VERSION 5.7 ;
BUSBITCHARS "[]" ;
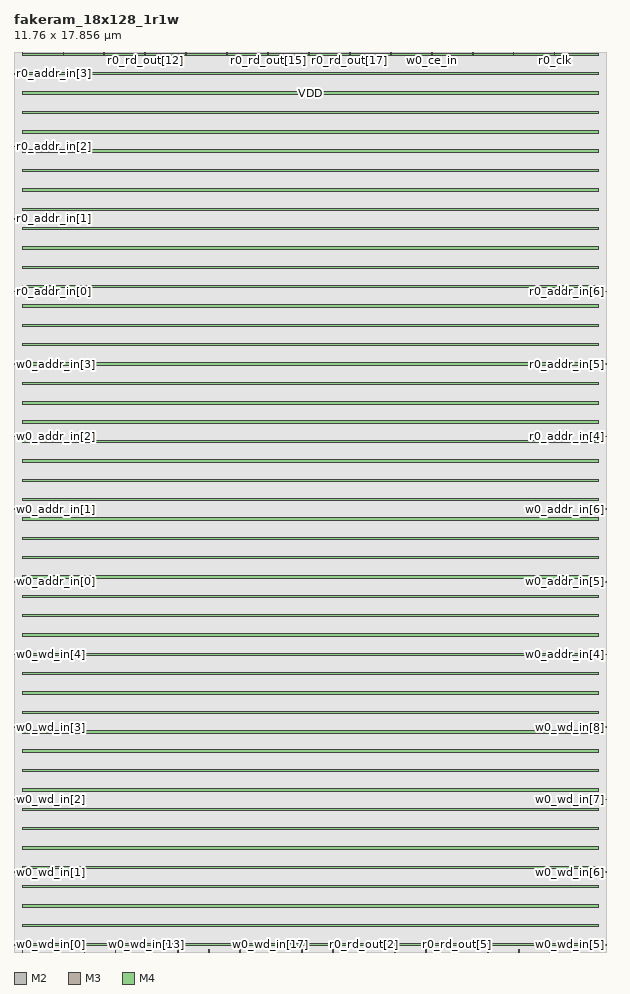
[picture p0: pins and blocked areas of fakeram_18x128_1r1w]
MACRO fakeram_18x128_1r1w
  FOREIGN fakeram_18x128_1r1w 0 0 ;
  SYMMETRY X Y R90 ;
  SIZE 11.760 BY 17.856 ;
  CLASS BLOCK ;
  PIN w0_wd_in[0]
    DIRECTION INPUT ;
    USE SIGNAL ;
    SHAPE ABUTMENT ;
    PORT
      LAYER M2 ;
      RECT 0.000 0.138 0.036 0.150 ;
    END
  END w0_wd_in[0]
  PIN w0_wd_in[1]
    DIRECTION INPUT ;
    USE SIGNAL ;
    SHAPE ABUTMENT ;
    PORT
      LAYER M2 ;
      RECT 0.000 1.578 0.036 1.590 ;
    END
  END w0_wd_in[1]
  PIN w0_wd_in[2]
    DIRECTION INPUT ;
    USE SIGNAL ;
    SHAPE ABUTMENT ;
    PORT
      LAYER M2 ;
      RECT 0.000 3.018 0.036 3.030 ;
    END
  END w0_wd_in[2]
  PIN w0_wd_in[3]
    DIRECTION INPUT ;
    USE SIGNAL ;
    SHAPE ABUTMENT ;
    PORT
      LAYER M2 ;
      RECT 0.000 4.458 0.036 4.470 ;
    END
  END w0_wd_in[3]
  PIN w0_wd_in[4]
    DIRECTION INPUT ;
    USE SIGNAL ;
    SHAPE ABUTMENT ;
    PORT
      LAYER M2 ;
      RECT 0.000 5.898 0.036 5.910 ;
    END
  END w0_wd_in[4]
  PIN w0_wd_in[5]
    DIRECTION INPUT ;
    USE SIGNAL ;
    SHAPE ABUTMENT ;
    PORT
      LAYER M2 ;
      RECT 11.724 0.138 11.760 0.150 ;
    END
  END w0_wd_in[5]
  PIN w0_wd_in[6]
    DIRECTION INPUT ;
    USE SIGNAL ;
    SHAPE ABUTMENT ;
    PORT
      LAYER M2 ;
      RECT 11.724 1.578 11.760 1.590 ;
    END
  END w0_wd_in[6]
  PIN w0_wd_in[7]
    DIRECTION INPUT ;
    USE SIGNAL ;
    SHAPE ABUTMENT ;
    PORT
      LAYER M2 ;
      RECT 11.724 3.018 11.760 3.030 ;
    END
  END w0_wd_in[7]
  PIN w0_wd_in[8]
    DIRECTION INPUT ;
    USE SIGNAL ;
    SHAPE ABUTMENT ;
    PORT
      LAYER M2 ;
      RECT 11.724 4.458 11.760 4.470 ;
    END
  END w0_wd_in[8]
  PIN w0_wd_in[9]
    DIRECTION INPUT ;
    USE SIGNAL ;
    SHAPE ABUTMENT ;
    PORT
      LAYER M3 ;
      RECT 0.161 0.000 0.175 0.042 ;
    END
  END w0_wd_in[9]
  PIN w0_wd_in[10]
    DIRECTION INPUT ;
    USE SIGNAL ;
    SHAPE ABUTMENT ;
    PORT
      LAYER M3 ;
      RECT 0.777 0.000 0.791 0.042 ;
    END
  END w0_wd_in[10]
  PIN w0_wd_in[11]
    DIRECTION INPUT ;
    USE SIGNAL ;
    SHAPE ABUTMENT ;
    PORT
      LAYER M3 ;
      RECT 1.393 0.000 1.407 0.042 ;
    END
  END w0_wd_in[11]
  PIN w0_wd_in[12]
    DIRECTION INPUT ;
    USE SIGNAL ;
    SHAPE ABUTMENT ;
    PORT
      LAYER M3 ;
      RECT 2.009 0.000 2.023 0.042 ;
    END
  END w0_wd_in[12]
  PIN w0_wd_in[13]
    DIRECTION INPUT ;
    USE SIGNAL ;
    SHAPE ABUTMENT ;
    PORT
      LAYER M3 ;
      RECT 2.625 0.000 2.639 0.042 ;
    END
  END w0_wd_in[13]
  PIN w0_wd_in[14]
    DIRECTION INPUT ;
    USE SIGNAL ;
    SHAPE ABUTMENT ;
    PORT
      LAYER M3 ;
      RECT 3.241 0.000 3.255 0.042 ;
    END
  END w0_wd_in[14]
  PIN w0_wd_in[15]
    DIRECTION INPUT ;
    USE SIGNAL ;
    SHAPE ABUTMENT ;
    PORT
      LAYER M3 ;
      RECT 3.857 0.000 3.871 0.042 ;
    END
  END w0_wd_in[15]
  PIN w0_wd_in[16]
    DIRECTION INPUT ;
    USE SIGNAL ;
    SHAPE ABUTMENT ;
    PORT
      LAYER M3 ;
      RECT 4.473 0.000 4.487 0.042 ;
    END
  END w0_wd_in[16]
  PIN w0_wd_in[17]
    DIRECTION INPUT ;
    USE SIGNAL ;
    SHAPE ABUTMENT ;
    PORT
      LAYER M3 ;
      RECT 5.089 0.000 5.103 0.042 ;
    END
  END w0_wd_in[17]
  PIN r0_rd_out[0]
    DIRECTION OUTPUT ;
    USE SIGNAL ;
    SHAPE ABUTMENT ;
    PORT
      LAYER M3 ;
      RECT 5.705 0.000 5.719 0.042 ;
    END
  END r0_rd_out[0]
  PIN r0_rd_out[1]
    DIRECTION OUTPUT ;
    USE SIGNAL ;
    SHAPE ABUTMENT ;
    PORT
      LAYER M3 ;
      RECT 6.321 0.000 6.335 0.042 ;
    END
  END r0_rd_out[1]
  PIN r0_rd_out[2]
    DIRECTION OUTPUT ;
    USE SIGNAL ;
    SHAPE ABUTMENT ;
    PORT
      LAYER M3 ;
      RECT 6.937 0.000 6.951 0.042 ;
    END
  END r0_rd_out[2]
  PIN r0_rd_out[3]
    DIRECTION OUTPUT ;
    USE SIGNAL ;
    SHAPE ABUTMENT ;
    PORT
      LAYER M3 ;
      RECT 7.553 0.000 7.567 0.042 ;
    END
  END r0_rd_out[3]
  PIN r0_rd_out[4]
    DIRECTION OUTPUT ;
    USE SIGNAL ;
    SHAPE ABUTMENT ;
    PORT
      LAYER M3 ;
      RECT 8.169 0.000 8.183 0.042 ;
    END
  END r0_rd_out[4]
  PIN r0_rd_out[5]
    DIRECTION OUTPUT ;
    USE SIGNAL ;
    SHAPE ABUTMENT ;
    PORT
      LAYER M3 ;
      RECT 8.785 0.000 8.799 0.042 ;
    END
  END r0_rd_out[5]
  PIN r0_rd_out[6]
    DIRECTION OUTPUT ;
    USE SIGNAL ;
    SHAPE ABUTMENT ;
    PORT
      LAYER M3 ;
      RECT 9.401 0.000 9.415 0.042 ;
    END
  END r0_rd_out[6]
  PIN r0_rd_out[7]
    DIRECTION OUTPUT ;
    USE SIGNAL ;
    SHAPE ABUTMENT ;
    PORT
      LAYER M3 ;
      RECT 10.017 0.000 10.031 0.042 ;
    END
  END r0_rd_out[7]
  PIN r0_rd_out[8]
    DIRECTION OUTPUT ;
    USE SIGNAL ;
    SHAPE ABUTMENT ;
    PORT
      LAYER M3 ;
      RECT 10.633 0.000 10.647 0.042 ;
    END
  END r0_rd_out[8]
  PIN r0_rd_out[9]
    DIRECTION OUTPUT ;
    USE SIGNAL ;
    SHAPE ABUTMENT ;
    PORT
      LAYER M3 ;
      RECT 0.161 17.814 0.175 17.856 ;
    END
  END r0_rd_out[9]
  PIN r0_rd_out[10]
    DIRECTION OUTPUT ;
    USE SIGNAL ;
    SHAPE ABUTMENT ;
    PORT
      LAYER M3 ;
      RECT 0.973 17.814 0.987 17.856 ;
    END
  END r0_rd_out[10]
  PIN r0_rd_out[11]
    DIRECTION OUTPUT ;
    USE SIGNAL ;
    SHAPE ABUTMENT ;
    PORT
      LAYER M3 ;
      RECT 1.785 17.814 1.799 17.856 ;
    END
  END r0_rd_out[11]
  PIN r0_rd_out[12]
    DIRECTION OUTPUT ;
    USE SIGNAL ;
    SHAPE ABUTMENT ;
    PORT
      LAYER M3 ;
      RECT 2.597 17.814 2.611 17.856 ;
    END
  END r0_rd_out[12]
  PIN r0_rd_out[13]
    DIRECTION OUTPUT ;
    USE SIGNAL ;
    SHAPE ABUTMENT ;
    PORT
      LAYER M3 ;
      RECT 3.409 17.814 3.423 17.856 ;
    END
  END r0_rd_out[13]
  PIN r0_rd_out[14]
    DIRECTION OUTPUT ;
    USE SIGNAL ;
    SHAPE ABUTMENT ;
    PORT
      LAYER M3 ;
      RECT 4.221 17.814 4.235 17.856 ;
    END
  END r0_rd_out[14]
  PIN r0_rd_out[15]
    DIRECTION OUTPUT ;
    USE SIGNAL ;
    SHAPE ABUTMENT ;
    PORT
      LAYER M3 ;
      RECT 5.033 17.814 5.047 17.856 ;
    END
  END r0_rd_out[15]
  PIN r0_rd_out[16]
    DIRECTION OUTPUT ;
    USE SIGNAL ;
    SHAPE ABUTMENT ;
    PORT
      LAYER M3 ;
      RECT 5.845 17.814 5.859 17.856 ;
    END
  END r0_rd_out[16]
  PIN r0_rd_out[17]
    DIRECTION OUTPUT ;
    USE SIGNAL ;
    SHAPE ABUTMENT ;
    PORT
      LAYER M3 ;
      RECT 6.657 17.814 6.671 17.856 ;
    END
  END r0_rd_out[17]
  PIN w0_addr_in[0]
    DIRECTION INPUT ;
    USE SIGNAL ;
    SHAPE ABUTMENT ;
    PORT
      LAYER M2 ;
      RECT 0.000 7.338 0.036 7.350 ;
    END
  END w0_addr_in[0]
  PIN w0_addr_in[1]
    DIRECTION INPUT ;
    USE SIGNAL ;
    SHAPE ABUTMENT ;
    PORT
      LAYER M2 ;
      RECT 0.000 8.778 0.036 8.790 ;
    END
  END w0_addr_in[1]
  PIN w0_addr_in[2]
    DIRECTION INPUT ;
    USE SIGNAL ;
    SHAPE ABUTMENT ;
    PORT
      LAYER M2 ;
      RECT 0.000 10.218 0.036 10.230 ;
    END
  END w0_addr_in[2]
  PIN w0_addr_in[3]
    DIRECTION INPUT ;
    USE SIGNAL ;
    SHAPE ABUTMENT ;
    PORT
      LAYER M2 ;
      RECT 0.000 11.658 0.036 11.670 ;
    END
  END w0_addr_in[3]
  PIN w0_addr_in[4]
    DIRECTION INPUT ;
    USE SIGNAL ;
    SHAPE ABUTMENT ;
    PORT
      LAYER M2 ;
      RECT 11.724 5.898 11.760 5.910 ;
    END
  END w0_addr_in[4]
  PIN w0_addr_in[5]
    DIRECTION INPUT ;
    USE SIGNAL ;
    SHAPE ABUTMENT ;
    PORT
      LAYER M2 ;
      RECT 11.724 7.338 11.760 7.350 ;
    END
  END w0_addr_in[5]
  PIN w0_addr_in[6]
    DIRECTION INPUT ;
    USE SIGNAL ;
    SHAPE ABUTMENT ;
    PORT
      LAYER M2 ;
      RECT 11.724 8.778 11.760 8.790 ;
    END
  END w0_addr_in[6]
  PIN r0_addr_in[0]
    DIRECTION INPUT ;
    USE SIGNAL ;
    SHAPE ABUTMENT ;
    PORT
      LAYER M2 ;
      RECT 0.000 13.098 0.036 13.110 ;
    END
  END r0_addr_in[0]
  PIN r0_addr_in[1]
    DIRECTION INPUT ;
    USE SIGNAL ;
    SHAPE ABUTMENT ;
    PORT
      LAYER M2 ;
      RECT 0.000 14.538 0.036 14.550 ;
    END
  END r0_addr_in[1]
  PIN r0_addr_in[2]
    DIRECTION INPUT ;
    USE SIGNAL ;
    SHAPE ABUTMENT ;
    PORT
      LAYER M2 ;
      RECT 0.000 15.978 0.036 15.990 ;
    END
  END r0_addr_in[2]
  PIN r0_addr_in[3]
    DIRECTION INPUT ;
    USE SIGNAL ;
    SHAPE ABUTMENT ;
    PORT
      LAYER M2 ;
      RECT 0.000 17.418 0.036 17.430 ;
    END
  END r0_addr_in[3]
  PIN r0_addr_in[4]
    DIRECTION INPUT ;
    USE SIGNAL ;
    SHAPE ABUTMENT ;
    PORT
      LAYER M2 ;
      RECT 11.724 10.218 11.760 10.230 ;
    END
  END r0_addr_in[4]
  PIN r0_addr_in[5]
    DIRECTION INPUT ;
    USE SIGNAL ;
    SHAPE ABUTMENT ;
    PORT
      LAYER M2 ;
      RECT 11.724 11.658 11.760 11.670 ;
    END
  END r0_addr_in[5]
  PIN r0_addr_in[6]
    DIRECTION INPUT ;
    USE SIGNAL ;
    SHAPE ABUTMENT ;
    PORT
      LAYER M2 ;
      RECT 11.724 13.098 11.760 13.110 ;
    END
  END r0_addr_in[6]
  PIN w0_we_in
    DIRECTION INPUT ;
    USE SIGNAL ;
    SHAPE ABUTMENT ;
    PORT
      LAYER M3 ;
      RECT 7.469 17.814 7.483 17.856 ;
    END
  END w0_we_in
  PIN w0_ce_in
    DIRECTION INPUT ;
    USE SIGNAL ;
    SHAPE ABUTMENT ;
    PORT
      LAYER M3 ;
      RECT 8.281 17.814 8.295 17.856 ;
    END
  END w0_ce_in
  PIN w0_clk
    DIRECTION INPUT ;
    USE SIGNAL ;
    SHAPE ABUTMENT ;
    PORT
      LAYER M3 ;
      RECT 9.093 17.814 9.107 17.856 ;
    END
  END w0_clk
  PIN r0_ce_in
    DIRECTION INPUT ;
    USE SIGNAL ;
    SHAPE ABUTMENT ;
    PORT
      LAYER M3 ;
      RECT 9.905 17.814 9.919 17.856 ;
    END
  END r0_ce_in
  PIN r0_clk
    DIRECTION INPUT ;
    USE SIGNAL ;
    SHAPE ABUTMENT ;
    PORT
      LAYER M3 ;
      RECT 10.717 17.814 10.731 17.856 ;
    END
  END r0_clk
  PIN VSS
    DIRECTION INOUT ;
    USE GROUND ;
    PORT
      LAYER M4 ;
      RECT 0.168 0.120 11.592 0.168 ;
      RECT 0.168 0.504 11.592 0.552 ;
      RECT 0.168 0.888 11.592 0.936 ;
      RECT 0.168 1.272 11.592 1.320 ;
      RECT 0.168 1.656 11.592 1.704 ;
      RECT 0.168 2.040 11.592 2.088 ;
      RECT 0.168 2.424 11.592 2.472 ;
      RECT 0.168 2.808 11.592 2.856 ;
      RECT 0.168 3.192 11.592 3.240 ;
      RECT 0.168 3.576 11.592 3.624 ;
      RECT 0.168 3.960 11.592 4.008 ;
      RECT 0.168 4.344 11.592 4.392 ;
      RECT 0.168 4.728 11.592 4.776 ;
      RECT 0.168 5.112 11.592 5.160 ;
      RECT 0.168 5.496 11.592 5.544 ;
      RECT 0.168 5.880 11.592 5.928 ;
      RECT 0.168 6.264 11.592 6.312 ;
      RECT 0.168 6.648 11.592 6.696 ;
      RECT 0.168 7.032 11.592 7.080 ;
      RECT 0.168 7.416 11.592 7.464 ;
      RECT 0.168 7.800 11.592 7.848 ;
      RECT 0.168 8.184 11.592 8.232 ;
      RECT 0.168 8.568 11.592 8.616 ;
      RECT 0.168 8.952 11.592 9.000 ;
      RECT 0.168 9.336 11.592 9.384 ;
      RECT 0.168 9.720 11.592 9.768 ;
      RECT 0.168 10.104 11.592 10.152 ;
      RECT 0.168 10.488 11.592 10.536 ;
      RECT 0.168 10.872 11.592 10.920 ;
      RECT 0.168 11.256 11.592 11.304 ;
      RECT 0.168 11.640 11.592 11.688 ;
      RECT 0.168 12.024 11.592 12.072 ;
      RECT 0.168 12.408 11.592 12.456 ;
      RECT 0.168 12.792 11.592 12.840 ;
      RECT 0.168 13.176 11.592 13.224 ;
      RECT 0.168 13.560 11.592 13.608 ;
      RECT 0.168 13.944 11.592 13.992 ;
      RECT 0.168 14.328 11.592 14.376 ;
      RECT 0.168 14.712 11.592 14.760 ;
      RECT 0.168 15.096 11.592 15.144 ;
      RECT 0.168 15.480 11.592 15.528 ;
      RECT 0.168 15.864 11.592 15.912 ;
      RECT 0.168 16.248 11.592 16.296 ;
      RECT 0.168 16.632 11.592 16.680 ;
      RECT 0.168 17.016 11.592 17.064 ;
      RECT 0.168 17.400 11.592 17.448 ;
      RECT 0.168 17.784 11.592 17.832 ;
    END
  END VSS
  PIN VDD
    DIRECTION INOUT ;
    USE POWER ;
    PORT
      LAYER M4 ;
      RECT 0.168 0.120 11.592 0.168 ;
      RECT 0.168 0.504 11.592 0.552 ;
      RECT 0.168 0.888 11.592 0.936 ;
      RECT 0.168 1.272 11.592 1.320 ;
      RECT 0.168 1.656 11.592 1.704 ;
      RECT 0.168 2.040 11.592 2.088 ;
      RECT 0.168 2.424 11.592 2.472 ;
      RECT 0.168 2.808 11.592 2.856 ;
      RECT 0.168 3.192 11.592 3.240 ;
      RECT 0.168 3.576 11.592 3.624 ;
      RECT 0.168 3.960 11.592 4.008 ;
      RECT 0.168 4.344 11.592 4.392 ;
      RECT 0.168 4.728 11.592 4.776 ;
      RECT 0.168 5.112 11.592 5.160 ;
      RECT 0.168 5.496 11.592 5.544 ;
      RECT 0.168 5.880 11.592 5.928 ;
      RECT 0.168 6.264 11.592 6.312 ;
      RECT 0.168 6.648 11.592 6.696 ;
      RECT 0.168 7.032 11.592 7.080 ;
      RECT 0.168 7.416 11.592 7.464 ;
      RECT 0.168 7.800 11.592 7.848 ;
      RECT 0.168 8.184 11.592 8.232 ;
      RECT 0.168 8.568 11.592 8.616 ;
      RECT 0.168 8.952 11.592 9.000 ;
      RECT 0.168 9.336 11.592 9.384 ;
      RECT 0.168 9.720 11.592 9.768 ;
      RECT 0.168 10.104 11.592 10.152 ;
      RECT 0.168 10.488 11.592 10.536 ;
      RECT 0.168 10.872 11.592 10.920 ;
      RECT 0.168 11.256 11.592 11.304 ;
      RECT 0.168 11.640 11.592 11.688 ;
      RECT 0.168 12.024 11.592 12.072 ;
      RECT 0.168 12.408 11.592 12.456 ;
      RECT 0.168 12.792 11.592 12.840 ;
      RECT 0.168 13.176 11.592 13.224 ;
      RECT 0.168 13.560 11.592 13.608 ;
      RECT 0.168 13.944 11.592 13.992 ;
      RECT 0.168 14.328 11.592 14.376 ;
      RECT 0.168 14.712 11.592 14.760 ;
      RECT 0.168 15.096 11.592 15.144 ;
      RECT 0.168 15.480 11.592 15.528 ;
      RECT 0.168 15.864 11.592 15.912 ;
      RECT 0.168 16.248 11.592 16.296 ;
      RECT 0.168 16.632 11.592 16.680 ;
      RECT 0.168 17.016 11.592 17.064 ;
      RECT 0.168 17.400 11.592 17.448 ;
      RECT 0.168 17.784 11.592 17.832 ;
    END
  END VDD
  OBS
    LAYER M1 ;
    RECT 0 0 11.760 17.856 ;
    LAYER M2 ;
    RECT 0 0 11.760 17.856 ;
    LAYER M3 ;
    RECT 0 0 11.760 17.856 ;
    LAYER M4 ;
    RECT 0 0 11.760 17.856 ;
  END
END fakeram_18x128_1r1w

END LIBRARY
